VERSION 5.7 ;
  NOWIREEXTENSIONATPIN ON ;
  DIVIDERCHAR "/" ;
  BUSBITCHARS "[]" ;
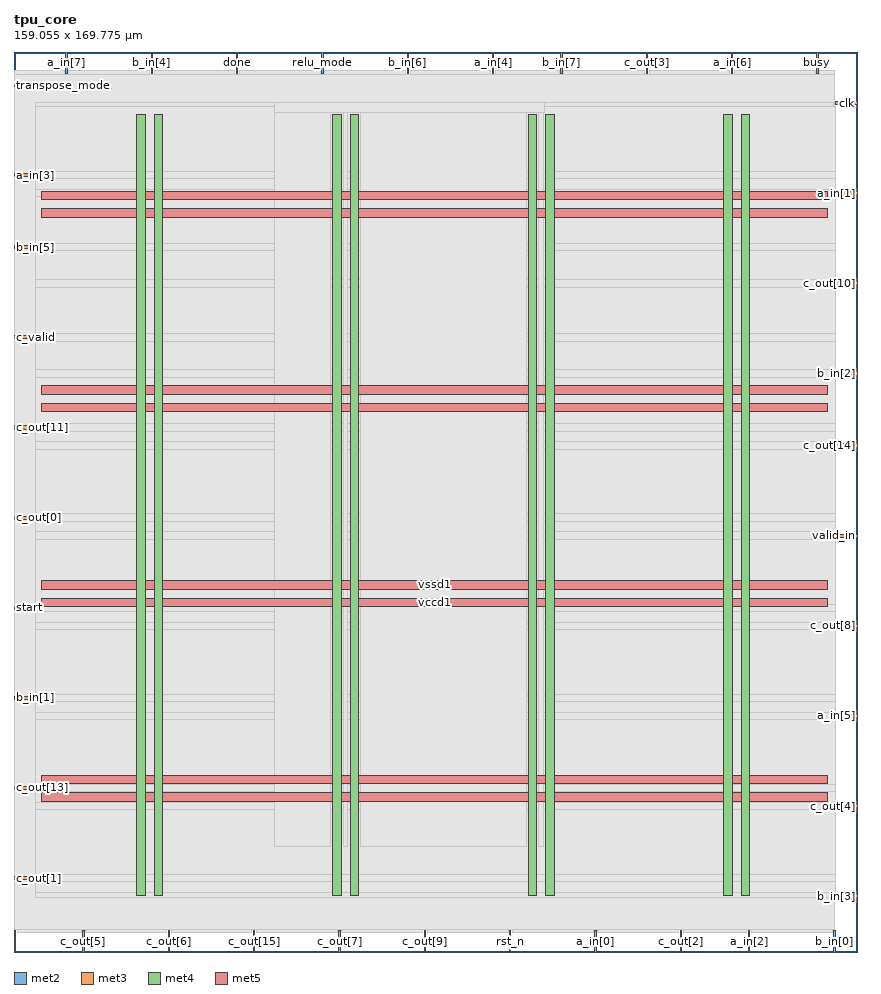
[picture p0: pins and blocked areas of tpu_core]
MACRO tpu_core
  CLASS BLOCK ;
  FOREIGN tpu_core ;
  ORIGIN 0.000 0.000 ;
  SIZE 159.055 BY 169.775 ;
  PIN a_in[0]
    DIRECTION INPUT ;
    USE SIGNAL ;
    ANTENNAGATEAREA 0.213000 ;
    PORT
      LAYER met2 ;
        RECT 109.570 0.000 109.850 4.000 ;
    END
  END a_in[0]
  PIN a_in[1]
    DIRECTION INPUT ;
    USE SIGNAL ;
    ANTENNAGATEAREA 0.126000 ;
    PORT
      LAYER met3 ;
        RECT 155.055 142.840 159.055 143.440 ;
    END
  END a_in[1]
  PIN a_in[2]
    DIRECTION INPUT ;
    USE SIGNAL ;
    ANTENNAGATEAREA 0.213000 ;
    PORT
      LAYER met2 ;
        RECT 138.550 0.000 138.830 4.000 ;
    END
  END a_in[2]
  PIN a_in[3]
    DIRECTION INPUT ;
    USE SIGNAL ;
    ANTENNAGATEAREA 0.213000 ;
    PORT
      LAYER met3 ;
        RECT 0.000 146.240 4.000 146.840 ;
    END
  END a_in[3]
  PIN a_in[4]
    DIRECTION INPUT ;
    USE SIGNAL ;
    ANTENNAGATEAREA 0.196500 ;
    PORT
      LAYER met2 ;
        RECT 90.250 165.775 90.530 169.775 ;
    END
  END a_in[4]
  PIN a_in[5]
    DIRECTION INPUT ;
    USE SIGNAL ;
    ANTENNAGATEAREA 0.213000 ;
    PORT
      LAYER met3 ;
        RECT 155.055 44.240 159.055 44.840 ;
    END
  END a_in[5]
  PIN a_in[6]
    DIRECTION INPUT ;
    USE SIGNAL ;
    ANTENNAGATEAREA 0.196500 ;
    PORT
      LAYER met2 ;
        RECT 135.330 165.775 135.610 169.775 ;
    END
  END a_in[6]
  PIN a_in[7]
    DIRECTION INPUT ;
    USE SIGNAL ;
    ANTENNAGATEAREA 0.196500 ;
    PORT
      LAYER met2 ;
        RECT 9.750 165.775 10.030 169.775 ;
    END
  END a_in[7]
  PIN b_in[0]
    DIRECTION INPUT ;
    USE SIGNAL ;
    ANTENNAGATEAREA 0.196500 ;
    PORT
      LAYER met2 ;
        RECT 154.650 0.000 154.930 4.000 ;
    END
  END b_in[0]
  PIN b_in[1]
    DIRECTION INPUT ;
    USE SIGNAL ;
    ANTENNAGATEAREA 0.213000 ;
    PORT
      LAYER met3 ;
        RECT 0.000 47.640 4.000 48.240 ;
    END
  END b_in[1]
  PIN b_in[2]
    DIRECTION INPUT ;
    USE SIGNAL ;
    ANTENNAGATEAREA 0.196500 ;
    PORT
      LAYER met3 ;
        RECT 155.055 108.840 159.055 109.440 ;
    END
  END b_in[2]
  PIN b_in[3]
    DIRECTION INPUT ;
    USE SIGNAL ;
    ANTENNAGATEAREA 0.196500 ;
    PORT
      LAYER met3 ;
        RECT 155.055 10.240 159.055 10.840 ;
    END
  END b_in[3]
  PIN b_in[4]
    DIRECTION INPUT ;
    USE SIGNAL ;
    ANTENNAGATEAREA 0.196500 ;
    PORT
      LAYER met2 ;
        RECT 25.850 165.775 26.130 169.775 ;
    END
  END b_in[4]
  PIN b_in[5]
    DIRECTION INPUT ;
    USE SIGNAL ;
    ANTENNAGATEAREA 0.196500 ;
    PORT
      LAYER met3 ;
        RECT 0.000 132.640 4.000 133.240 ;
    END
  END b_in[5]
  PIN b_in[6]
    DIRECTION INPUT ;
    USE SIGNAL ;
    ANTENNAGATEAREA 0.196500 ;
    PORT
      LAYER met2 ;
        RECT 74.150 165.775 74.430 169.775 ;
    END
  END b_in[6]
  PIN b_in[7]
    DIRECTION INPUT ;
    USE SIGNAL ;
    ANTENNAGATEAREA 0.196500 ;
    PORT
      LAYER met2 ;
        RECT 103.130 165.775 103.410 169.775 ;
    END
  END b_in[7]
  PIN busy
    DIRECTION OUTPUT TRISTATE ;
    USE SIGNAL ;
    ANTENNADIFFAREA 0.795200 ;
    PORT
      LAYER met2 ;
        RECT 151.430 165.775 151.710 169.775 ;
    END
  END busy
  PIN c_out[0]
    DIRECTION OUTPUT TRISTATE ;
    USE SIGNAL ;
    ANTENNADIFFAREA 0.795200 ;
    PORT
      LAYER met3 ;
        RECT 0.000 81.640 4.000 82.240 ;
    END
  END c_out[0]
  PIN c_out[10]
    DIRECTION OUTPUT TRISTATE ;
    USE SIGNAL ;
    ANTENNADIFFAREA 0.795200 ;
    PORT
      LAYER met3 ;
        RECT 155.055 125.840 159.055 126.440 ;
    END
  END c_out[10]
  PIN c_out[11]
    DIRECTION OUTPUT TRISTATE ;
    USE SIGNAL ;
    ANTENNADIFFAREA 0.795200 ;
    PORT
      LAYER met3 ;
        RECT 0.000 98.640 4.000 99.240 ;
    END
  END c_out[11]
  PIN c_out[12]
    DIRECTION OUTPUT TRISTATE ;
    USE SIGNAL ;
    ANTENNADIFFAREA 0.795200 ;
    PORT
      LAYER met2 ;
        RECT 0.090 0.000 0.370 4.000 ;
    END
  END c_out[12]
  PIN c_out[13]
    DIRECTION OUTPUT TRISTATE ;
    USE SIGNAL ;
    ANTENNADIFFAREA 0.795200 ;
    PORT
      LAYER met3 ;
        RECT 0.000 30.640 4.000 31.240 ;
    END
  END c_out[13]
  PIN c_out[14]
    DIRECTION OUTPUT TRISTATE ;
    USE SIGNAL ;
    ANTENNADIFFAREA 0.795200 ;
    PORT
      LAYER met3 ;
        RECT 155.055 95.240 159.055 95.840 ;
    END
  END c_out[14]
  PIN c_out[15]
    DIRECTION OUTPUT TRISTATE ;
    USE SIGNAL ;
    ANTENNADIFFAREA 0.795200 ;
    PORT
      LAYER met2 ;
        RECT 45.170 0.000 45.450 4.000 ;
    END
  END c_out[15]
  PIN c_out[1]
    DIRECTION OUTPUT TRISTATE ;
    USE SIGNAL ;
    ANTENNADIFFAREA 0.795200 ;
    PORT
      LAYER met3 ;
        RECT 0.000 13.640 4.000 14.240 ;
    END
  END c_out[1]
  PIN c_out[2]
    DIRECTION OUTPUT TRISTATE ;
    USE SIGNAL ;
    ANTENNADIFFAREA 0.795200 ;
    PORT
      LAYER met2 ;
        RECT 125.670 0.000 125.950 4.000 ;
    END
  END c_out[2]
  PIN c_out[3]
    DIRECTION OUTPUT TRISTATE ;
    USE SIGNAL ;
    ANTENNADIFFAREA 0.795200 ;
    PORT
      LAYER met2 ;
        RECT 119.230 165.775 119.510 169.775 ;
    END
  END c_out[3]
  PIN c_out[4]
    DIRECTION OUTPUT TRISTATE ;
    USE SIGNAL ;
    ANTENNADIFFAREA 0.795200 ;
    PORT
      LAYER met3 ;
        RECT 155.055 27.240 159.055 27.840 ;
    END
  END c_out[4]
  PIN c_out[5]
    DIRECTION OUTPUT TRISTATE ;
    USE SIGNAL ;
    ANTENNADIFFAREA 0.795200 ;
    PORT
      LAYER met2 ;
        RECT 12.970 0.000 13.250 4.000 ;
    END
  END c_out[5]
  PIN c_out[6]
    DIRECTION OUTPUT TRISTATE ;
    USE SIGNAL ;
    ANTENNADIFFAREA 0.795200 ;
    PORT
      LAYER met2 ;
        RECT 29.070 0.000 29.350 4.000 ;
    END
  END c_out[6]
  PIN c_out[7]
    DIRECTION OUTPUT TRISTATE ;
    USE SIGNAL ;
    ANTENNADIFFAREA 0.795200 ;
    PORT
      LAYER met2 ;
        RECT 61.270 0.000 61.550 4.000 ;
    END
  END c_out[7]
  PIN c_out[8]
    DIRECTION OUTPUT TRISTATE ;
    USE SIGNAL ;
    ANTENNADIFFAREA 0.795200 ;
    PORT
      LAYER met3 ;
        RECT 155.055 61.240 159.055 61.840 ;
    END
  END c_out[8]
  PIN c_out[9]
    DIRECTION OUTPUT TRISTATE ;
    USE SIGNAL ;
    ANTENNADIFFAREA 0.795200 ;
    PORT
      LAYER met2 ;
        RECT 77.370 0.000 77.650 4.000 ;
    END
  END c_out[9]
  PIN c_valid
    DIRECTION OUTPUT TRISTATE ;
    USE SIGNAL ;
    ANTENNADIFFAREA 0.795200 ;
    PORT
      LAYER met3 ;
        RECT 0.000 115.640 4.000 116.240 ;
    END
  END c_valid
  PIN clk
    DIRECTION INPUT ;
    USE SIGNAL ;
    ANTENNAGATEAREA 0.852000 ;
    PORT
      LAYER met3 ;
        RECT 155.055 159.840 159.055 160.440 ;
    END
  END clk
  PIN done
    DIRECTION OUTPUT TRISTATE ;
    USE SIGNAL ;
    ANTENNADIFFAREA 0.795200 ;
    PORT
      LAYER met2 ;
        RECT 41.950 165.775 42.230 169.775 ;
    END
  END done
  PIN relu_mode
    DIRECTION INPUT ;
    USE SIGNAL ;
    ANTENNAGATEAREA 0.213000 ;
    PORT
      LAYER met2 ;
        RECT 58.050 165.775 58.330 169.775 ;
    END
  END relu_mode
  PIN rst_n
    DIRECTION INPUT ;
    USE SIGNAL ;
    ANTENNAGATEAREA 0.196500 ;
    PORT
      LAYER met2 ;
        RECT 93.470 0.000 93.750 4.000 ;
    END
  END rst_n
  PIN start
    DIRECTION INPUT ;
    USE SIGNAL ;
    ANTENNAGATEAREA 0.213000 ;
    PORT
      LAYER met3 ;
        RECT 0.000 64.640 4.000 65.240 ;
    END
  END start
  PIN transpose_mode
    DIRECTION INPUT ;
    USE SIGNAL ;
    PORT
      LAYER met3 ;
        RECT 0.000 163.240 4.000 163.840 ;
    END
  END transpose_mode
  PIN valid_in
    DIRECTION INPUT ;
    USE SIGNAL ;
    PORT
      LAYER met3 ;
        RECT 155.055 78.240 159.055 78.840 ;
    END
  END valid_in
  PIN vccd1
    DIRECTION INOUT ;
    USE POWER ;
    PORT
      LAYER met4 ;
        RECT 23.175 10.640 24.775 158.000 ;
    END
    PORT
      LAYER met4 ;
        RECT 60.090 10.640 61.690 158.000 ;
    END
    PORT
      LAYER met4 ;
        RECT 97.005 10.640 98.605 158.000 ;
    END
    PORT
      LAYER met4 ;
        RECT 133.920 10.640 135.520 158.000 ;
    END
    PORT
      LAYER met5 ;
        RECT 5.280 28.440 153.420 30.040 ;
    END
    PORT
      LAYER met5 ;
        RECT 5.280 65.160 153.420 66.760 ;
    END
    PORT
      LAYER met5 ;
        RECT 5.280 101.880 153.420 103.480 ;
    END
    PORT
      LAYER met5 ;
        RECT 5.280 138.600 153.420 140.200 ;
    END
  END vccd1
  PIN vssd1
    DIRECTION INOUT ;
    USE GROUND ;
    PORT
      LAYER met4 ;
        RECT 26.475 10.640 28.075 158.000 ;
    END
    PORT
      LAYER met4 ;
        RECT 63.390 10.640 64.990 158.000 ;
    END
    PORT
      LAYER met4 ;
        RECT 100.305 10.640 101.905 158.000 ;
    END
    PORT
      LAYER met4 ;
        RECT 137.220 10.640 138.820 158.000 ;
    END
    PORT
      LAYER met5 ;
        RECT 5.280 31.740 153.420 33.340 ;
    END
    PORT
      LAYER met5 ;
        RECT 5.280 68.460 153.420 70.060 ;
    END
    PORT
      LAYER met5 ;
        RECT 5.280 105.180 153.420 106.780 ;
    END
    PORT
      LAYER met5 ;
        RECT 5.280 141.900 153.420 143.500 ;
    END
  END vssd1
  OBS
      LAYER li1 ;
        RECT 5.520 10.795 153.180 157.845 ;
      LAYER met1 ;
        RECT 0.070 10.640 154.030 158.400 ;
      LAYER met2 ;
        RECT 0.100 165.495 9.470 166.330 ;
        RECT 10.310 165.495 25.570 166.330 ;
        RECT 26.410 165.495 41.670 166.330 ;
        RECT 42.510 165.495 57.770 166.330 ;
        RECT 58.610 165.495 73.870 166.330 ;
        RECT 74.710 165.495 89.970 166.330 ;
        RECT 90.810 165.495 102.850 166.330 ;
        RECT 103.690 165.495 118.950 166.330 ;
        RECT 119.790 165.495 135.050 166.330 ;
        RECT 135.890 165.495 151.150 166.330 ;
        RECT 151.990 165.495 154.860 166.330 ;
        RECT 0.100 4.280 154.860 165.495 ;
        RECT 0.650 3.670 12.690 4.280 ;
        RECT 13.530 3.670 28.790 4.280 ;
        RECT 29.630 3.670 44.890 4.280 ;
        RECT 45.730 3.670 60.990 4.280 ;
        RECT 61.830 3.670 77.090 4.280 ;
        RECT 77.930 3.670 93.190 4.280 ;
        RECT 94.030 3.670 109.290 4.280 ;
        RECT 110.130 3.670 125.390 4.280 ;
        RECT 126.230 3.670 138.270 4.280 ;
        RECT 139.110 3.670 154.370 4.280 ;
      LAYER met3 ;
        RECT 3.990 159.440 154.655 160.300 ;
        RECT 3.990 147.240 155.055 159.440 ;
        RECT 4.400 145.840 155.055 147.240 ;
        RECT 3.990 143.840 155.055 145.840 ;
        RECT 3.990 142.440 154.655 143.840 ;
        RECT 3.990 133.640 155.055 142.440 ;
        RECT 4.400 132.240 155.055 133.640 ;
        RECT 3.990 126.840 155.055 132.240 ;
        RECT 3.990 125.440 154.655 126.840 ;
        RECT 3.990 116.640 155.055 125.440 ;
        RECT 4.400 115.240 155.055 116.640 ;
        RECT 3.990 109.840 155.055 115.240 ;
        RECT 3.990 108.440 154.655 109.840 ;
        RECT 3.990 99.640 155.055 108.440 ;
        RECT 4.400 98.240 155.055 99.640 ;
        RECT 3.990 96.240 155.055 98.240 ;
        RECT 3.990 94.840 154.655 96.240 ;
        RECT 3.990 82.640 155.055 94.840 ;
        RECT 4.400 81.240 155.055 82.640 ;
        RECT 3.990 79.240 155.055 81.240 ;
        RECT 3.990 77.840 154.655 79.240 ;
        RECT 3.990 65.640 155.055 77.840 ;
        RECT 4.400 64.240 155.055 65.640 ;
        RECT 3.990 62.240 155.055 64.240 ;
        RECT 3.990 60.840 154.655 62.240 ;
        RECT 3.990 48.640 155.055 60.840 ;
        RECT 4.400 47.240 155.055 48.640 ;
        RECT 3.990 45.240 155.055 47.240 ;
        RECT 3.990 43.840 154.655 45.240 ;
        RECT 3.990 31.640 155.055 43.840 ;
        RECT 4.400 30.240 155.055 31.640 ;
        RECT 3.990 28.240 155.055 30.240 ;
        RECT 3.990 26.840 154.655 28.240 ;
        RECT 3.990 14.640 155.055 26.840 ;
        RECT 4.400 13.240 155.055 14.640 ;
        RECT 3.990 11.240 155.055 13.240 ;
        RECT 3.990 10.375 154.655 11.240 ;
      LAYER met4 ;
        RECT 49.055 158.400 99.985 160.305 ;
        RECT 49.055 19.895 59.690 158.400 ;
        RECT 62.090 19.895 62.990 158.400 ;
        RECT 65.390 19.895 96.605 158.400 ;
        RECT 99.005 19.895 99.905 158.400 ;
  END
END tpu_core
END LIBRARY

